! (c) 2009  Infineon Technologies AG, Munich
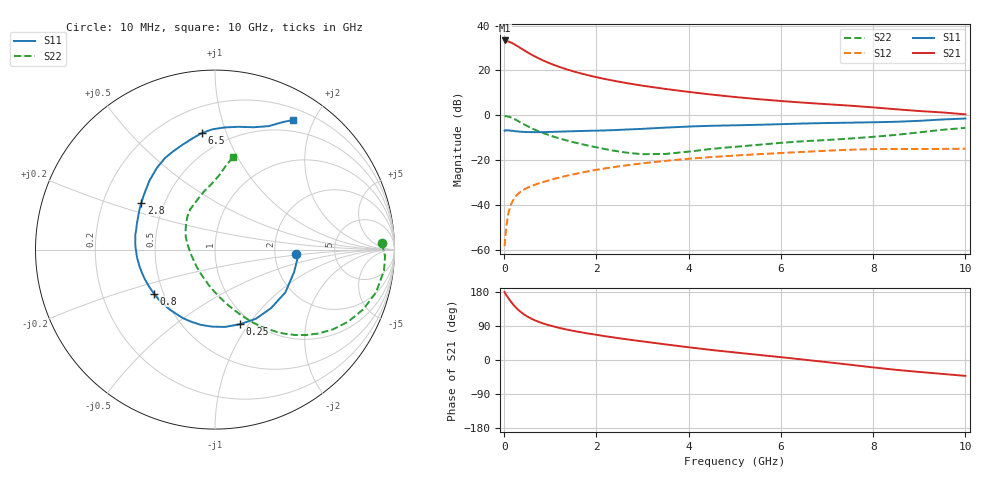
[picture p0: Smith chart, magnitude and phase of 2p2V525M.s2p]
! Infineon Technologies  Discrete & RF Semiconductors
! BFP420
! VCE =  2.5 V,  IC =  25 mA
! Common Emitter S-Parameters:  Nov 2009
# GHz  S  MA  R  50
!  f  S11  S21  S12  S22
! GHz  MAG  ANG  MAG  ANG  MAG  ANG  MAG  ANG
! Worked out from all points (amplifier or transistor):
!   46 points, 10 MHz to 10 GHz, reference 50 ohm
!   highest |S21| = 33.4 dB at 10 MHz (marker M1)
!   |S21| within 3 dB of that: start of sweep to 324.4 MHz
!   unconditionally stable (mu >= 1): 1.662 GHz to end of sweep
!   at 300 MHz: K = 0.36, MSG = 32.9 dB, |S12| = -35.1 dB
!   at 1.7 GHz: K = 1.01, MAG = 21.5 dB, |S12| = -25.5 dB
!   at 10 GHz: K = 1.06, MAG = 6.1 dB, |S12| = -14.9 dB
!   lowest NFmin = 1.38 dB at 900 MHz
!   S11 on the Smith chart (normalised r, x): 10 MHz: 2.62, -0.17; 250 MHz: 0.88, -0.91; 800 MHz: 0.44, -0.26; 2.8 GHz: 0.37, +0.25; 6.5 GHz: 0.36, +0.83; 10 GHz: 0.34, +1.72
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0.01  0.4502 -3.3  46.53 179.2  0.0012 105.6  0.9307 2.1
0.02  0.4616 -6.4  45.42 176.2  0.0017 90.4  0.9482 -2.2
0.05  0.4585 -15.5  44.99 170.7  0.0035 85.8  0.9487 -7.1
0.1  0.4588 -31.3  43.84 161.8  0.0071 79.2  0.9283 -14.9
0.15  0.4514 -46.1  41.76 153.4  0.0103 74.6  0.8904 -22.0
0.2  0.4476 -59.4  39.34 145.9  0.013 70.6  0.8437 -28.4
0.25  0.4383 -71.6  36.63 139.0  0.0155 66.9  0.794 -34.0
0.3  0.4346 -82.5  34.15 133.0  0.0176 64.4  0.7437 -38.9
0.4  0.4266 -100.7  29.46 123.0  0.0211 60.4  0.6515 -46.9
0.5  0.4213 -115.2  25.49 115.0  0.024 58.2  0.5739 -53.1
0.6  0.419 -126.9  22.27 108.4  0.0266 56.8  0.5107 -58.2
0.8  0.4195 -144.3  17.49 98.4  0.0313 55.7  0.4171 -66.0
1  0.4243 -157.1  14.25 90.8  0.036 55.4  0.3516 -72.6
1.2  0.4303 -166.8  11.93 84.5  0.0407 55.2  0.3034 -78.7
1.7  0.4459 175.0  8.379 72.5  0.053 53.6  0.2241 -93.3
2.8  0.4865 147.4  4.919 52.3  0.0799 46.1  0.1408 -135.5
3.5  0.5294 133.8  3.853 41.2  0.096 39.9  0.1369 -169.6
5.5  0.6116 107.2  2.286 13.7  0.1348 21.5  0.2184 137.4
6.5  0.6537 96.4  1.905 0.9  0.1524 12.3  0.2636 121.7
7  0.6703 91.2  1.761 -5.7  0.1616 7.5  0.2801 114.1
8.5  0.7148 72.5  1.357 -26.0  0.1757 -9.5  0.3648 93.2
10  0.8443 58.9  1.046 -41.9  0.1791 -20.8  0.523 79.1
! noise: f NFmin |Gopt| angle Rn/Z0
0.9  1.38  0.22  -154  0.13
1.8  1.65  0.29  -143  0.13
2.4  1.81  0.26  -138  0.17
3  1.83  0.34  -129  0.18
4  1.97  0.45  -112  0.27
5  2.4  0.49  -95  0.44
6  2.85  0.54  -84  0.65
